# Generated by OpenFakeRAM
VERSION 5.7 ;
BUSBITCHARS "[]" ;
PROPERTYDEFINITIONS
  MACRO width INTEGER ;
  MACRO depth INTEGER ;
  MACRO banks INTEGER ;
END PROPERTYDEFINITIONS
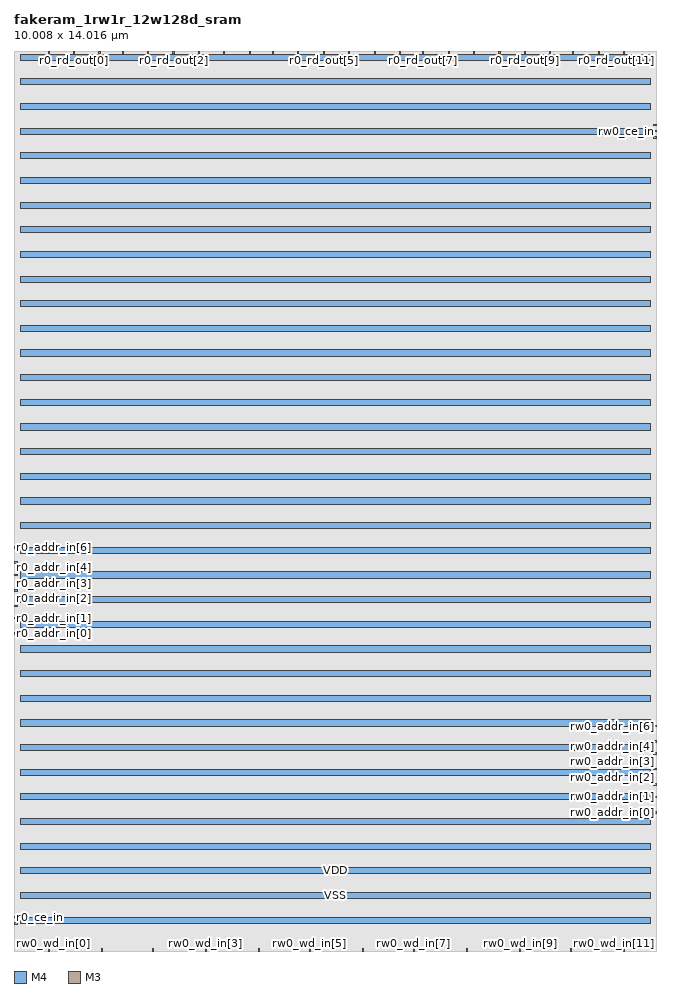
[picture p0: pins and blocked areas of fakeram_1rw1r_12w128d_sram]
MACRO fakeram_1rw1r_12w128d_sram
  PROPERTY width 12 ;
  PROPERTY depth 128 ;
  PROPERTY banks 1 ;
  FOREIGN fakeram_1rw1r_12w128d_sram 0 0 ;
  SYMMETRY X Y R90 ;
  SIZE 10.008 BY 14.016 ;
  CLASS BLOCK ;
  PIN r0_clk
    DIRECTION INPUT ;
    USE SIGNAL ;
    SHAPE ABUTMENT ;
    PORT
      LAYER M4 ;
      RECT 0.000 0.420 0.048 0.444 ;
    END
  END r0_clk
  PIN r0_ce_in
    DIRECTION INPUT ;
    USE SIGNAL ;
    SHAPE ABUTMENT ;
    PORT
      LAYER M4 ;
      RECT 0.000 0.516 0.048 0.540 ;
    END
  END r0_ce_in
  PIN r0_addr_in[0]
    DIRECTION INPUT ;
    USE SIGNAL ;
    SHAPE ABUTMENT ;
    PORT
      LAYER M4 ;
      RECT 0.000 4.932 0.048 4.956 ;
    END
  END r0_addr_in[0]
  PIN r0_addr_in[1]
    DIRECTION INPUT ;
    USE SIGNAL ;
    SHAPE ABUTMENT ;
    PORT
      LAYER M4 ;
      RECT 0.000 5.172 0.048 5.196 ;
    END
  END r0_addr_in[1]
  PIN r0_addr_in[2]
    DIRECTION INPUT ;
    USE SIGNAL ;
    SHAPE ABUTMENT ;
    PORT
      LAYER M4 ;
      RECT 0.000 5.364 0.048 5.388 ;
    END
  END r0_addr_in[2]
  PIN r0_addr_in[3]
    DIRECTION INPUT ;
    USE SIGNAL ;
    SHAPE ABUTMENT ;
    PORT
      LAYER M4 ;
      RECT 0.000 5.604 0.048 5.628 ;
    END
  END r0_addr_in[3]
  PIN r0_addr_in[4]
    DIRECTION INPUT ;
    USE SIGNAL ;
    SHAPE ABUTMENT ;
    PORT
      LAYER M4 ;
      RECT 0.000 5.844 0.048 5.868 ;
    END
  END r0_addr_in[4]
  PIN r0_addr_in[5]
    DIRECTION INPUT ;
    USE SIGNAL ;
    SHAPE ABUTMENT ;
    PORT
      LAYER M4 ;
      RECT 0.000 6.036 0.048 6.060 ;
    END
  END r0_addr_in[5]
  PIN r0_addr_in[6]
    DIRECTION INPUT ;
    USE SIGNAL ;
    SHAPE ABUTMENT ;
    PORT
      LAYER M4 ;
      RECT 0.000 6.276 0.048 6.300 ;
    END
  END r0_addr_in[6]
  PIN rw0_rd_out[0]
    DIRECTION OUTPUT ;
    USE SIGNAL ;
    SHAPE ABUTMENT ;
    PORT
      LAYER M3 ;
      RECT 0.531 13.980 0.549 14.016 ;
    END
  END rw0_rd_out[0]
  PIN r0_rd_out[0]
    DIRECTION OUTPUT ;
    USE SIGNAL ;
    SHAPE ABUTMENT ;
    PORT
      LAYER M3 ;
      RECT 0.927 13.980 0.945 14.016 ;
    END
  END r0_rd_out[0]
  PIN rw0_rd_out[1]
    DIRECTION OUTPUT ;
    USE SIGNAL ;
    SHAPE ABUTMENT ;
    PORT
      LAYER M3 ;
      RECT 1.323 13.980 1.341 14.016 ;
    END
  END rw0_rd_out[1]
  PIN r0_rd_out[1]
    DIRECTION OUTPUT ;
    USE SIGNAL ;
    SHAPE ABUTMENT ;
    PORT
      LAYER M3 ;
      RECT 1.683 13.980 1.701 14.016 ;
    END
  END r0_rd_out[1]
  PIN rw0_rd_out[2]
    DIRECTION OUTPUT ;
    USE SIGNAL ;
    SHAPE ABUTMENT ;
    PORT
      LAYER M3 ;
      RECT 2.079 13.980 2.097 14.016 ;
    END
  END rw0_rd_out[2]
  PIN r0_rd_out[2]
    DIRECTION OUTPUT ;
    USE SIGNAL ;
    SHAPE ABUTMENT ;
    PORT
      LAYER M3 ;
      RECT 2.475 13.980 2.493 14.016 ;
    END
  END r0_rd_out[2]
  PIN rw0_rd_out[3]
    DIRECTION OUTPUT ;
    USE SIGNAL ;
    SHAPE ABUTMENT ;
    PORT
      LAYER M3 ;
      RECT 2.871 13.980 2.889 14.016 ;
    END
  END rw0_rd_out[3]
  PIN r0_rd_out[3]
    DIRECTION OUTPUT ;
    USE SIGNAL ;
    SHAPE ABUTMENT ;
    PORT
      LAYER M3 ;
      RECT 3.267 13.980 3.285 14.016 ;
    END
  END r0_rd_out[3]
  PIN rw0_rd_out[4]
    DIRECTION OUTPUT ;
    USE SIGNAL ;
    SHAPE ABUTMENT ;
    PORT
      LAYER M3 ;
      RECT 3.663 13.980 3.681 14.016 ;
    END
  END rw0_rd_out[4]
  PIN r0_rd_out[4]
    DIRECTION OUTPUT ;
    USE SIGNAL ;
    SHAPE ABUTMENT ;
    PORT
      LAYER M3 ;
      RECT 4.023 13.980 4.041 14.016 ;
    END
  END r0_rd_out[4]
  PIN rw0_rd_out[5]
    DIRECTION OUTPUT ;
    USE SIGNAL ;
    SHAPE ABUTMENT ;
    PORT
      LAYER M3 ;
      RECT 4.419 13.980 4.437 14.016 ;
    END
  END rw0_rd_out[5]
  PIN r0_rd_out[5]
    DIRECTION OUTPUT ;
    USE SIGNAL ;
    SHAPE ABUTMENT ;
    PORT
      LAYER M3 ;
      RECT 4.815 13.980 4.833 14.016 ;
    END
  END r0_rd_out[5]
  PIN rw0_rd_out[6]
    DIRECTION OUTPUT ;
    USE SIGNAL ;
    SHAPE ABUTMENT ;
    PORT
      LAYER M3 ;
      RECT 5.211 13.980 5.229 14.016 ;
    END
  END rw0_rd_out[6]
  PIN r0_rd_out[6]
    DIRECTION OUTPUT ;
    USE SIGNAL ;
    SHAPE ABUTMENT ;
    PORT
      LAYER M3 ;
      RECT 5.607 13.980 5.625 14.016 ;
    END
  END r0_rd_out[6]
  PIN rw0_rd_out[7]
    DIRECTION OUTPUT ;
    USE SIGNAL ;
    SHAPE ABUTMENT ;
    PORT
      LAYER M3 ;
      RECT 6.003 13.980 6.021 14.016 ;
    END
  END rw0_rd_out[7]
  PIN r0_rd_out[7]
    DIRECTION OUTPUT ;
    USE SIGNAL ;
    SHAPE ABUTMENT ;
    PORT
      LAYER M3 ;
      RECT 6.363 13.980 6.381 14.016 ;
    END
  END r0_rd_out[7]
  PIN rw0_rd_out[8]
    DIRECTION OUTPUT ;
    USE SIGNAL ;
    SHAPE ABUTMENT ;
    PORT
      LAYER M3 ;
      RECT 6.759 13.980 6.777 14.016 ;
    END
  END rw0_rd_out[8]
  PIN r0_rd_out[8]
    DIRECTION OUTPUT ;
    USE SIGNAL ;
    SHAPE ABUTMENT ;
    PORT
      LAYER M3 ;
      RECT 7.155 13.980 7.173 14.016 ;
    END
  END r0_rd_out[8]
  PIN rw0_rd_out[9]
    DIRECTION OUTPUT ;
    USE SIGNAL ;
    SHAPE ABUTMENT ;
    PORT
      LAYER M3 ;
      RECT 7.551 13.980 7.569 14.016 ;
    END
  END rw0_rd_out[9]
  PIN r0_rd_out[9]
    DIRECTION OUTPUT ;
    USE SIGNAL ;
    SHAPE ABUTMENT ;
    PORT
      LAYER M3 ;
      RECT 7.947 13.980 7.965 14.016 ;
    END
  END r0_rd_out[9]
  PIN rw0_rd_out[10]
    DIRECTION OUTPUT ;
    USE SIGNAL ;
    SHAPE ABUTMENT ;
    PORT
      LAYER M3 ;
      RECT 8.343 13.980 8.361 14.016 ;
    END
  END rw0_rd_out[10]
  PIN r0_rd_out[10]
    DIRECTION OUTPUT ;
    USE SIGNAL ;
    SHAPE ABUTMENT ;
    PORT
      LAYER M3 ;
      RECT 8.703 13.980 8.721 14.016 ;
    END
  END r0_rd_out[10]
  PIN rw0_rd_out[11]
    DIRECTION OUTPUT ;
    USE SIGNAL ;
    SHAPE ABUTMENT ;
    PORT
      LAYER M3 ;
      RECT 9.099 13.980 9.117 14.016 ;
    END
  END rw0_rd_out[11]
  PIN r0_rd_out[11]
    DIRECTION OUTPUT ;
    USE SIGNAL ;
    SHAPE ABUTMENT ;
    PORT
      LAYER M3 ;
      RECT 9.495 13.980 9.513 14.016 ;
    END
  END r0_rd_out[11]
  PIN rw0_clk
    DIRECTION INPUT ;
    USE SIGNAL ;
    SHAPE ABUTMENT ;
    PORT
      LAYER M4 ;
      RECT 9.960 12.660 10.008 12.684 ;
    END
  END rw0_clk
  PIN rw0_ce_in
    DIRECTION INPUT ;
    USE SIGNAL ;
    SHAPE ABUTMENT ;
    PORT
      LAYER M4 ;
      RECT 9.960 12.756 10.008 12.780 ;
    END
  END rw0_ce_in
  PIN rw0_we_in
    DIRECTION INPUT ;
    USE SIGNAL ;
    SHAPE ABUTMENT ;
    PORT
      LAYER M4 ;
      RECT 9.960 12.852 10.008 12.876 ;
    END
  END rw0_we_in
  PIN rw0_addr_in[0]
    DIRECTION INPUT ;
    USE SIGNAL ;
    SHAPE ABUTMENT ;
    PORT
      LAYER M4 ;
      RECT 9.960 2.148 10.008 2.172 ;
    END
  END rw0_addr_in[0]
  PIN rw0_addr_in[1]
    DIRECTION INPUT ;
    USE SIGNAL ;
    SHAPE ABUTMENT ;
    PORT
      LAYER M4 ;
      RECT 9.960 2.388 10.008 2.412 ;
    END
  END rw0_addr_in[1]
  PIN rw0_addr_in[2]
    DIRECTION INPUT ;
    USE SIGNAL ;
    SHAPE ABUTMENT ;
    PORT
      LAYER M4 ;
      RECT 9.960 2.580 10.008 2.604 ;
    END
  END rw0_addr_in[2]
  PIN rw0_addr_in[3]
    DIRECTION INPUT ;
    USE SIGNAL ;
    SHAPE ABUTMENT ;
    PORT
      LAYER M4 ;
      RECT 9.960 2.820 10.008 2.844 ;
    END
  END rw0_addr_in[3]
  PIN rw0_addr_in[4]
    DIRECTION INPUT ;
    USE SIGNAL ;
    SHAPE ABUTMENT ;
    PORT
      LAYER M4 ;
      RECT 9.960 3.060 10.008 3.084 ;
    END
  END rw0_addr_in[4]
  PIN rw0_addr_in[5]
    DIRECTION INPUT ;
    USE SIGNAL ;
    SHAPE ABUTMENT ;
    PORT
      LAYER M4 ;
      RECT 9.960 3.252 10.008 3.276 ;
    END
  END rw0_addr_in[5]
  PIN rw0_addr_in[6]
    DIRECTION INPUT ;
    USE SIGNAL ;
    SHAPE ABUTMENT ;
    PORT
      LAYER M4 ;
      RECT 9.960 3.492 10.008 3.516 ;
    END
  END rw0_addr_in[6]
  PIN rw0_wd_in[0]
    DIRECTION INPUT ;
    USE SIGNAL ;
    SHAPE ABUTMENT ;
    PORT
      LAYER M3 ;
      RECT 0.531 0.000 0.549 0.036 ;
    END
  END rw0_wd_in[0]
  PIN rw0_wd_in[1]
    DIRECTION INPUT ;
    USE SIGNAL ;
    SHAPE ABUTMENT ;
    PORT
      LAYER M3 ;
      RECT 1.359 0.000 1.377 0.036 ;
    END
  END rw0_wd_in[1]
  PIN rw0_wd_in[2]
    DIRECTION INPUT ;
    USE SIGNAL ;
    SHAPE ABUTMENT ;
    PORT
      LAYER M3 ;
      RECT 2.151 0.000 2.169 0.036 ;
    END
  END rw0_wd_in[2]
  PIN rw0_wd_in[3]
    DIRECTION INPUT ;
    USE SIGNAL ;
    SHAPE ABUTMENT ;
    PORT
      LAYER M3 ;
      RECT 2.979 0.000 2.997 0.036 ;
    END
  END rw0_wd_in[3]
  PIN rw0_wd_in[4]
    DIRECTION INPUT ;
    USE SIGNAL ;
    SHAPE ABUTMENT ;
    PORT
      LAYER M3 ;
      RECT 3.807 0.000 3.825 0.036 ;
    END
  END rw0_wd_in[4]
  PIN rw0_wd_in[5]
    DIRECTION INPUT ;
    USE SIGNAL ;
    SHAPE ABUTMENT ;
    PORT
      LAYER M3 ;
      RECT 4.599 0.000 4.617 0.036 ;
    END
  END rw0_wd_in[5]
  PIN rw0_wd_in[6]
    DIRECTION INPUT ;
    USE SIGNAL ;
    SHAPE ABUTMENT ;
    PORT
      LAYER M3 ;
      RECT 5.427 0.000 5.445 0.036 ;
    END
  END rw0_wd_in[6]
  PIN rw0_wd_in[7]
    DIRECTION INPUT ;
    USE SIGNAL ;
    SHAPE ABUTMENT ;
    PORT
      LAYER M3 ;
      RECT 6.219 0.000 6.237 0.036 ;
    END
  END rw0_wd_in[7]
  PIN rw0_wd_in[8]
    DIRECTION INPUT ;
    USE SIGNAL ;
    SHAPE ABUTMENT ;
    PORT
      LAYER M3 ;
      RECT 7.047 0.000 7.065 0.036 ;
    END
  END rw0_wd_in[8]
  PIN rw0_wd_in[9]
    DIRECTION INPUT ;
    USE SIGNAL ;
    SHAPE ABUTMENT ;
    PORT
      LAYER M3 ;
      RECT 7.875 0.000 7.893 0.036 ;
    END
  END rw0_wd_in[9]
  PIN rw0_wd_in[10]
    DIRECTION INPUT ;
    USE SIGNAL ;
    SHAPE ABUTMENT ;
    PORT
      LAYER M3 ;
      RECT 8.667 0.000 8.685 0.036 ;
    END
  END rw0_wd_in[10]
  PIN rw0_wd_in[11]
    DIRECTION INPUT ;
    USE SIGNAL ;
    SHAPE ABUTMENT ;
    PORT
      LAYER M3 ;
      RECT 9.495 0.000 9.513 0.036 ;
    END
  END rw0_wd_in[11]
  PIN VSS
    DIRECTION INOUT ;
    USE GROUND ;
    PORT
      LAYER M4 ;
      RECT 0.096 0.816 9.912 0.912 ;
      RECT 0.096 1.584 9.912 1.680 ;
      RECT 0.096 2.352 9.912 2.448 ;
      RECT 0.096 3.120 9.912 3.216 ;
      RECT 0.096 3.888 9.912 3.984 ;
      RECT 0.096 4.656 9.912 4.752 ;
      RECT 0.096 5.424 9.912 5.520 ;
      RECT 0.096 6.192 9.912 6.288 ;
      RECT 0.096 6.960 9.912 7.056 ;
      RECT 0.096 7.728 9.912 7.824 ;
      RECT 0.096 8.496 9.912 8.592 ;
      RECT 0.096 9.264 9.912 9.360 ;
      RECT 0.096 10.032 9.912 10.128 ;
      RECT 0.096 10.800 9.912 10.896 ;
      RECT 0.096 11.568 9.912 11.664 ;
      RECT 0.096 12.336 9.912 12.432 ;
      RECT 0.096 13.104 9.912 13.200 ;
      RECT 0.096 13.872 9.912 13.968 ;
    END
  END VSS
  PIN VDD
    DIRECTION INOUT ;
    USE POWER ;
    PORT
      LAYER M4 ;
      RECT 0.096 0.432 9.912 0.528 ;
      RECT 0.096 1.200 9.912 1.296 ;
      RECT 0.096 1.968 9.912 2.064 ;
      RECT 0.096 2.736 9.912 2.832 ;
      RECT 0.096 3.504 9.912 3.600 ;
      RECT 0.096 4.272 9.912 4.368 ;
      RECT 0.096 5.040 9.912 5.136 ;
      RECT 0.096 5.808 9.912 5.904 ;
      RECT 0.096 6.576 9.912 6.672 ;
      RECT 0.096 7.344 9.912 7.440 ;
      RECT 0.096 8.112 9.912 8.208 ;
      RECT 0.096 8.880 9.912 8.976 ;
      RECT 0.096 9.648 9.912 9.744 ;
      RECT 0.096 10.416 9.912 10.512 ;
      RECT 0.096 11.184 9.912 11.280 ;
      RECT 0.096 11.952 9.912 12.048 ;
      RECT 0.096 12.720 9.912 12.816 ;
      RECT 0.096 13.488 9.912 13.584 ;
    END
  END VDD
  OBS
    LAYER M1 ;
    RECT 0 0 10.008 14.016 ;
    LAYER M2 ;
    RECT 0 0 10.008 14.016 ;
    LAYER M3 ;
    RECT 0 0 10.008 14.016 ;
    LAYER M4 ;
    RECT 0 0 10.008 14.016 ;
  END
END fakeram_1rw1r_12w128d_sram

END LIBRARY
